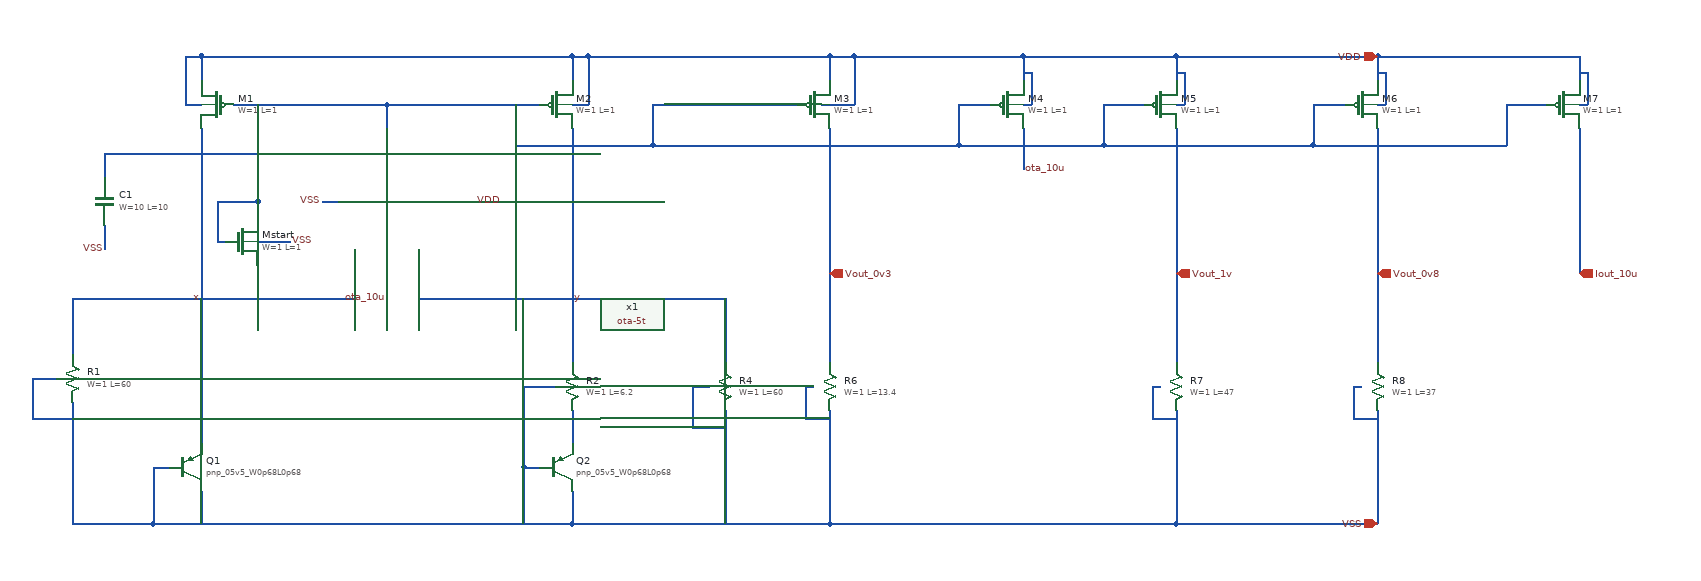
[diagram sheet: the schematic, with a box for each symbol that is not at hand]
v {xschem version=3.4.6 file_version=1.2}
G {}
K {}
V {}
S {}
E {}
N -80 -320 110 -320 {lab=#net1}
N -330 -320 -310 -320 {lab=VDD}
N -330 -380 -330 -320 {lab=VDD}
N -330 -380 -310 -380 {lab=VDD}
N -310 -380 -310 -350 {lab=VDD}
N 150 -320 170 -320 {lab=VDD}
N 170 -380 170 -320 {lab=VDD}
N 150 -380 170 -380 {lab=VDD}
N 150 -380 150 -350 {lab=VDD}
N -310 -290 -310 0 {lab=x}
N 150 -290 150 0 {lab=y}
N -310 0 -310 100 {lab=x}
N 150 60 150 100 {lab=#net2}
N -370 130 -350 130 {lab=VSS}
N -370 130 -370 200 {lab=VSS}
N -180 200 150 200 {lab=VSS}
N 150 160 150 200 {lab=VSS}
N -310 160 -310 200 {lab=VSS}
N 90 130 110 130 {lab=VSS}
N 90 130 90 200 {lab=VSS}
N -120 -380 150 -380 {lab=VDD}
N 80 -320 80 -270 {lab=#net1}
N 80 -270 250 -270 {lab=#net1}
N 250 -320 250 -270 {lab=#net1}
N 470 -380 470 -350 {lab=VDD}
N 470 -320 500 -320 {lab=VDD}
N 500 -380 500 -320 {lab=VDD}
N 470 -380 500 -380 {lab=VDD}
N 470 -290 470 0 {lab=Vout_0v3}
N -470 50 -470 200 {lab=VSS}
N -470 200 -370 200 {lab=VSS}
N 340 60 340 200 {lab=VSS}
N -270 -320 -80 -320 {lab=#net1}
N -310 -380 -120 -380 {lab=VDD}
N -370 200 -180 200 {lab=VSS}
N 470 60 470 200 {lab=VSS}
N -470 -80 -470 -10 {lab=x}
N 340 -80 340 0 {lab=y}
N -20 -200 30 -200 {lab=VDD}
N -80 -320 -80 -290 {lab=#net1}
N -120 -140 -120 -80 {lab=x}
N -310 -80 -120 -80 {lab=x}
N -40 -140 -40 -80 {lab=y}
N -40 -80 150 -80 {lab=y}
N -80 -140 -80 -80 {lab=ota_10u}
N -240 -120 -240 -80 {lab=x}
N -290 -150 -280 -150 {lab=#net1}
N -290 -200 -290 -150 {lab=#net1}
N -290 -200 -240 -200 {lab=#net1}
N -240 -200 -240 -180 {lab=#net1}
N -240 -320 -240 -200 {lab=#net1}
N -240 -150 -200 -150 {lab=VSS}
N -470 -80 -320 -80 {lab=x}
N -320 -80 -310 -80 {lab=x}
N 110 30 130 30 {lab=VSS}
N 90 30 110 30 {lab=VSS}
N 310 30 320 30 {lab=VSS}
N 300 30 310 30 {lab=VSS}
N -520 20 -490 20 {lab=VSS}
N -520 20 -520 70 {lab=VSS}
N -520 70 -470 70 {lab=VSS}
N 440 30 450 30 {lab=VSS}
N 440 30 440 70 {lab=VSS}
N 440 70 470 70 {lab=VSS}
N 250 -320 430 -320 {lab=#net1}
N 150 200 270 200 {lab=VSS}
N 270 200 470 200 {lab=VSS}
N 170 -380 470 -380 {lab=VDD}
N 300 30 300 80 {lab=VSS}
N 300 80 340 80 {lab=VSS}
N 90 30 90 130 {lab=VSS}
N 150 -80 340 -80 {lab=y}
N -160 -200 -140 -200 {lab=VSS}
N 460 -320 470 -320 {lab=VDD}
N -430 -260 -430 -230 {lab=#net1}
N -430 -260 -240 -260 {lab=#net1}
N -430 -170 -430 -140 {lab=VSS}
N 250 -270 630 -270 {lab=#net1}
N 630 -320 630 -270 {lab=#net1}
N 630 -320 670 -320 {lab=#net1}
N 500 -380 710 -380 {lab=VDD}
N 710 -380 710 -350 {lab=VDD}
N 710 -320 720 -320 {lab=VDD}
N 720 -360 720 -320 {lab=VDD}
N 710 -360 720 -360 {lab=VDD}
N 710 -290 710 -240 {lab=ota_10u}
N 900 -380 900 -350 {lab=VDD}
N 900 -320 910 -320 {lab=VDD}
N 910 -360 910 -320 {lab=VDD}
N 900 -360 910 -360 {lab=VDD}
N 900 -290 900 0 {lab=Vout_1v}
N 900 60 900 200 {lab=VSS}
N 870 30 880 30 {lab=VSS}
N 870 30 870 70 {lab=VSS}
N 870 70 900 70 {lab=VSS}
N 470 200 900 200 {lab=VSS}
N 710 -380 900 -380 {lab=VDD}
N 630 -270 810 -270 {lab=#net1}
N 810 -320 810 -270 {lab=#net1}
N 810 -320 860 -320 {lab=#net1}
N 1150 -320 1160 -320 {lab=VDD}
N 1160 -360 1160 -320 {lab=VDD}
N 1150 -360 1160 -360 {lab=VDD}
N 900 -380 1150 -380 {lab=VDD}
N 1150 -380 1150 -350 {lab=VDD}
N 810 -270 1070 -270 {lab=#net1}
N 1070 -320 1070 -270 {lab=#net1}
N 1070 -320 1110 -320 {lab=#net1}
N 1120 30 1130 30 {lab=VSS}
N 1120 30 1120 70 {lab=VSS}
N 1120 70 1150 70 {lab=VSS}
N 1150 -290 1150 -0 {lab=Vout_0v8}
N 900 200 1150 200 {lab=VSS}
N 1150 60 1150 200 {lab=VSS}
N 1400 -320 1410 -320 {lab=VDD}
N 1410 -360 1410 -320 {lab=VDD}
N 1400 -360 1410 -360 {lab=VDD}
N 1150 -380 1400 -380 {lab=VDD}
N 1400 -380 1400 -350 {lab=VDD}
N 1070 -270 1310 -270 {lab=#net1}
N 1310 -320 1310 -270 {lab=#net1}
N 1310 -320 1360 -320 {lab=#net1}
N 1400 -290 1400 -110 {lab=Iout_10u}
C {sky130_fd_pr/pnp_05v5.sym} -330 130 0 0 {name=Q1
model=pnp_05v5_W0p68L0p68
spiceprefix=X
m=4}
C {sky130_fd_pr/pnp_05v5.sym} 130 130 0 0 {name=Q2
model=pnp_05v5_W0p68L0p68
spiceprefix=X
m=32}
C {lab_pin.sym} -310 -80 0 0 {name=p4 sig_type=std_logic lab=x}
C {lab_pin.sym} 150 -80 2 0 {name=p5 sig_type=std_logic lab=y}
C {ngspice_probe.sym} 150 90 0 0 {name=r3}
C {ngspice_probe.sym} -180 -320 0 0 {name=r5}
C {ota-5t.sym} -80 -210 1 1 {name=x1}
C {lab_pin.sym} -160 -200 0 0 {name=p2 sig_type=std_logic lab=VSS}
C {lab_pin.sym} 30 -200 2 0 {name=p3 sig_type=std_logic lab=VDD}
C {sky130_fd_pr/pfet_01v8_lvt.sym} -290 -320 0 1 {name=M1
L=1
W=1
nf=1 mult=1
model=pfet_01v8_lvt
spiceprefix=X
}
C {sky130_fd_pr/pfet_01v8_lvt.sym} 130 -320 0 0 {name=M2
L=1
W=1
nf=1 mult=1
model=pfet_01v8_lvt
spiceprefix=X
}
C {sky130_fd_pr/pfet_01v8_lvt.sym} 450 -320 0 0 {name=M3
L=1
W=1
nf=1 mult=1
model=pfet_01v8_lvt
spiceprefix=X
}
C {sky130_fd_pr/nfet_01v8_lvt.sym} -260 -150 0 0 {name=Mstart
L=1
W=1
nf=1 mult=1
model=nfet_01v8_lvt
spiceprefix=X
}
C {lab_pin.sym} -200 -150 2 0 {name=p8 sig_type=std_logic lab=VSS}
C {sky130_fd_pr/res_xhigh_po.sym} -470 20 0 0 {name=R1
W=1
L=60
model=res_xhigh_po
spiceprefix=X
 mult=1}
C {sky130_fd_pr/res_xhigh_po.sym} 150 30 0 0 {name=R2
W=1
L=6.2
model=res_xhigh_po
spiceprefix=X
 mult=1}
C {sky130_fd_pr/res_xhigh_po.sym} 340 30 0 0 {name=R4
W=1
L=60
model=res_xhigh_po
spiceprefix=X
 mult=1}
C {sky130_fd_pr/res_xhigh_po.sym} 470 30 0 0 {name=R6
W=1
L=13.4
model=res_xhigh_po
spiceprefix=X
 mult=1}
C {sky130_fd_pr/cap_mim_m3_1.sym} -430 -200 0 0 {name=C1 model=cap_mim_m3_1 W=10 L=10 MF=1 spiceprefix=X}
C {lab_pin.sym} -430 -140 0 0 {name=p1 sig_type=std_logic lab=VSS}
C {sky130_fd_pr/pfet_01v8_lvt.sym} 690 -320 0 0 {name=M4
L=1
W=1
nf=1 mult=1
model=pfet_01v8_lvt
spiceprefix=X
}
C {lab_pin.sym} 710 -240 2 0 {name=p10 sig_type=std_logic lab=ota_10u}
C {iopin.sym} 1150 -380 0 0 {name=p7 lab=VDD}
C {opin.sym} 470 -110 0 0 {name=p9 lab=Vout_0v3}
C {sky130_fd_pr/pfet_01v8_lvt.sym} 880 -320 0 0 {name=M5
L=1
W=1
nf=1 mult=1
model=pfet_01v8_lvt
spiceprefix=X
}
C {sky130_fd_pr/res_xhigh_po.sym} 900 30 0 0 {name=R7
W=1
L=47
model=res_xhigh_po
spiceprefix=X
 mult=1}
C {iopin.sym} 1150 200 0 0 {name=p12 lab=VSS}
C {opin.sym} 900 -110 0 0 {name=p13 lab=Vout_1v}
C {sky130_fd_pr/pfet_01v8_lvt.sym} 1130 -320 0 0 {name=M6
L=1
W=1
nf=1 mult=1
model=pfet_01v8_lvt
spiceprefix=X
}
C {sky130_fd_pr/res_xhigh_po.sym} 1150 30 0 0 {name=R8
W=1
L=37
model=res_xhigh_po
spiceprefix=X
 mult=1}
C {opin.sym} 1150 -110 0 0 {name=p11 lab=Vout_0v8}
C {sky130_fd_pr/pfet_01v8_lvt.sym} 1380 -320 0 0 {name=M7
L=1
W=1
nf=1 mult=1
model=pfet_01v8_lvt
spiceprefix=X
}
C {opin.sym} 1400 -110 0 0 {name=p14 lab=Iout_10u}
C {lab_pin.sym} -80 -80 3 0 {name=p6 sig_type=std_logic lab=ota_10u}
